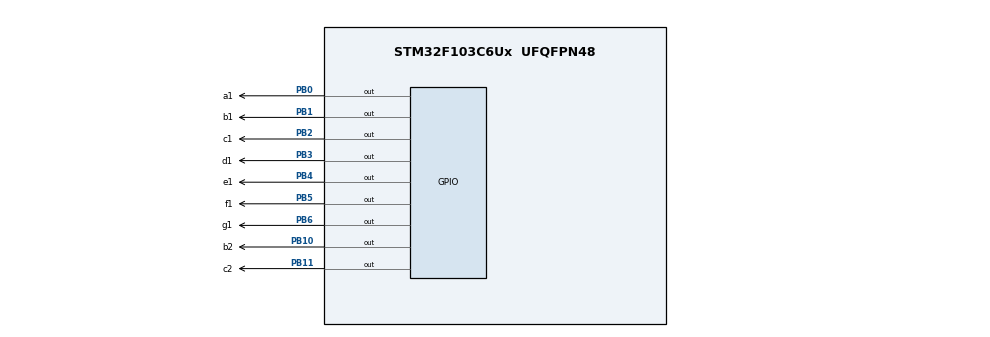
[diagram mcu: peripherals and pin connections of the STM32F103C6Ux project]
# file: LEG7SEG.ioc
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Mcu.Family=STM32F1
Mcu.Name=STM32F103C6Ux
Mcu.Package=UFQFPN48
NVIC.PriorityGroup=NVIC_PRIORITYGROUP_4
PB0.GPIO_Label=a1
PB0.Signal=GPIO_Output
PB1.GPIO_Label=b1
PB1.Signal=GPIO_Output
PB10.GPIO_Label=b2
PB10.Signal=GPIO_Output
PB11.GPIO_Label=c2
PB11.Signal=GPIO_Output
PB2.GPIO_Label=c1
PB2.Signal=GPIO_Output
PB3.GPIO_Label=d1
PB3.Signal=GPIO_Output
PB4.GPIO_Label=e1
PB4.Signal=GPIO_Output
PB5.GPIO_Label=f1
PB5.Signal=GPIO_Output
PB6.GPIO_Label=g1
PB6.Signal=GPIO_Output
ProjectManager.HeapSize=0x200
ProjectManager.StackSize=0x400
ProjectManager.TargetToolchain=STM32CubeIDE
RCC.APB1Freq_Value=8000000
RCC.APB2Freq_Value=8000000
VP_SYS_VS_ND.Mode=No_Debug
board=custom

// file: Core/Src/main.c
/* USER CODE BEGIN Header */
/**
  ******************************************************************************
  * @file           : main.c
  * @brief          : Main program body
  ******************************************************************************
  * @attention
  *
  * <h2><center>&copy; Copyright (c) 2022 STMicroelectronics.
  * All rights reserved.</center></h2>
  *
  * This software component is licensed by ST under BSD 3-Clause license,
  * the "License"; You may not use this file except in compliance with the
  * License. You may obtain a copy of the License at:
  *                        opensource.org/licenses/BSD-3-Clause
  *
  ******************************************************************************
  */
/* USER CODE END Header */
#include "main.h"

/* USER CODE BEGIN PD */
#define RED_timer 5
#define YELLOW_timer 2
#define GREEN_timer 3
/* USER CODE END PD */

void SystemClock_Config(void);
static void MX_GPIO_Init(void);

/* USER CODE BEGIN 0 */
void display7SEG(uint16_t Pin1, uint16_t Pin2, uint16_t Pin3, uint16_t Pin4, uint16_t Pin5, uint16_t Pin6, uint16_t Pin7,
				 GPIO_TypeDef* Port1, GPIO_TypeDef* Port2, GPIO_TypeDef* Port3, GPIO_TypeDef* Port4, GPIO_TypeDef* Port5, GPIO_TypeDef* Port6, GPIO_TypeDef* Port7,
				 int num) {
	switch(num) {
	case 0: //Number 0 is 0000001
		HAL_GPIO_WritePin(Port1, Pin1, RESET);
		HAL_GPIO_WritePin(Port2, Pin2, RESET);
		HAL_GPIO_WritePin(Port3, Pin3, RESET);
		HAL_GPIO_WritePin(Port4, Pin4, RESET);
		HAL_GPIO_WritePin(Port5, Pin5, RESET);
		HAL_GPIO_WritePin(Port6, Pin6, RESET);
		HAL_GPIO_WritePin(Port7, Pin7, SET);
		break;

	case 1: //Number 1 is 1001111
		HAL_GPIO_WritePin(Port1, Pin1, SET);
		HAL_GPIO_WritePin(Port2, Pin2, RESET);
		HAL_GPIO_WritePin(Port3, Pin3, RESET);
		HAL_GPIO_WritePin(Port4, Pin4, SET);
		HAL_GPIO_WritePin(Port5, Pin5, SET);
		HAL_GPIO_WritePin(Port6, Pin6, SET);
		HAL_GPIO_WritePin(Port7, Pin7, SET);
		break;

	case 2: //Number 2 is 0010010
		HAL_GPIO_WritePin(Port1, Pin1, RESET);
		HAL_GPIO_WritePin(Port2, Pin2, RESET);
		HAL_GPIO_WritePin(Port3, Pin3, SET);
		HAL_GPIO_WritePin(Port4, Pin4, RESET);
		HAL_GPIO_WritePin(Port5, Pin5, RESET);
		HAL_GPIO_WritePin(Port6, Pin6, SET);
		HAL_GPIO_WritePin(Port7, Pin7, RESET);
		break;

	case 3: //Number 3 is 0000110
		HAL_GPIO_WritePin(Port1, Pin1, RESET);
		HAL_GPIO_WritePin(Port2, Pin2, RESET);
		HAL_GPIO_WritePin(Port3, Pin3, RESET);
		HAL_GPIO_WritePin(Port4, Pin4, RESET);
		HAL_GPIO_WritePin(Port5, Pin5, SET);
		HAL_GPIO_WritePin(Port6, Pin6, SET);
		HAL_GPIO_WritePin(Port7, Pin7, RESET);
		break;

	case 4: //Number 4 is 1001100
		HAL_GPIO_WritePin(Port1, Pin1, SET);
		HAL_GPIO_WritePin(Port2, Pin2, RESET);
		HAL_GPIO_WritePin(Port3, Pin3, RESET);
		HAL_GPIO_WritePin(Port4, Pin4, SET);
		HAL_GPIO_WritePin(Port5, Pin5, SET);
		HAL_GPIO_WritePin(Port6, Pin6, RESET);
		HAL_GPIO_WritePin(Port7, Pin7, RESET);
		break;

	case 5: //Number 5 is 0100100
		HAL_GPIO_WritePin(Port1, Pin1, RESET);
		HAL_GPIO_WritePin(Port2, Pin2, SET);
		HAL_GPIO_WritePin(Port3, Pin3, RESET);
		HAL_GPIO_WritePin(Port4, Pin4, RESET);
		HAL_GPIO_WritePin(Port5, Pin5, SET);
		HAL_GPIO_WritePin(Port6, Pin6, RESET);
		HAL_GPIO_WritePin(Port7, Pin7, RESET);
		break;

	case 6: //Number 6 is 0100000
		HAL_GPIO_WritePin(Port1, Pin1, RESET);
		HAL_GPIO_WritePin(Port2, Pin2, SET);
		HAL_GPIO_WritePin(Port3, Pin3, RESET);
		HAL_GPIO_WritePin(Port4, Pin4, RESET);
		HAL_GPIO_WritePin(Port5, Pin5, RESET);
		HAL_GPIO_WritePin(Port6, Pin6, RESET);
		HAL_GPIO_WritePin(Port7, Pin7, RESET);
		break;

	case 7: //Number 7 is 0001111
		HAL_GPIO_WritePin(Port1, Pin1, RESET);
		HAL_GPIO_WritePin(Port2, Pin2, RESET);
		HAL_GPIO_WritePin(Port3, Pin3, RESET);
		HAL_GPIO_WritePin(Port4, Pin4, SET);
		HAL_GPIO_WritePin(Port5, Pin5, SET);
		HAL_GPIO_WritePin(Port6, Pin6, SET);
		HAL_GPIO_WritePin(Port7, Pin7, SET);
		break;

	case 8: //Number 8 is 0000000
		HAL_GPIO_WritePin(Port1, Pin1, RESET);
		HAL_GPIO_WritePin(Port2, Pin2, RESET);
		HAL_GPIO_WritePin(Port3, Pin3, RESET);
		HAL_GPIO_WritePin(Port4, Pin4, RESET);
		HAL_GPIO_WritePin(Port5, Pin5, RESET);
		HAL_GPIO_WritePin(Port6, Pin6, RESET);
		HAL_GPIO_WritePin(Port7, Pin7, RESET);
		break;

	case 9: //Number 9 is 0000100
		HAL_GPIO_WritePin(Port1, Pin1, RESET);
		HAL_GPIO_WritePin(Port2, Pin2, RESET);
		HAL_GPIO_WritePin(Port3, Pin3, RESET);
		HAL_GPIO_WritePin(Port4, Pin4, RESET);
		HAL_GPIO_WritePin(Port5, Pin5, SET);
		HAL_GPIO_WritePin(Port6, Pin6, RESET);
		HAL_GPIO_WritePin(Port7, Pin7, RESET);
		break;

	default: break;
	}
}
/* USER CODE END 0 */

int main(void)
{

  /* MCU Configuration--------------------------------------------------------*/

  /* Reset of all peripherals, Initializes the Flash interface and the Systick. */
  HAL_Init();

  /* Configure the system clock */
  SystemClock_Config();

  /* Initialize all configured peripherals */
  MX_GPIO_Init();

  /* Infinite loop */
  /* USER CODE BEGIN WHILE */
//4
//  int counter = 0;

  //5
  //Set the INITIAL status of each led
  int led_status1 = 1; // This is status of LEDs 1
  int led_status2 = 3; // This is status of LEDs 2
  /*
   * led_status = 1: red
   * led_status = 2: yellow
   * led_status = 3: green
   */

  //Set time for led's counter
  int red_counter1 = RED_timer;
  int yellow_counter1 = YELLOW_timer;
  int green_counter1 = GREEN_timer;

  int red_counter2 = RED_timer;
  int yellow_counter2 = YELLOW_timer;
  int green_counter2 = GREEN_timer;

  while (1) {
	  if (led_status1 == 1) //LED1 is RED
	    {
		  if (red_counter1 > 0) {
			  display7SEG(a1_Pin, b1_Pin, c1_Pin, d1_Pin, e1_Pin, f1_Pin, g1_Pin,
					  	  a1_GPIO_Port, b1_GPIO_Port, c1_GPIO_Port, d1_GPIO_Port, e1_GPIO_Port, f1_GPIO_Port, g1_GPIO_Port,
						  red_counter1--);
			  HAL_GPIO_WritePin(LED_RED1_GPIO_Port, LED_RED1_Pin, SET);
			  HAL_GPIO_WritePin(LED_YELLOW1_GPIO_Port, LED_YELLOW1_Pin, RESET);
			  HAL_GPIO_WritePin(LED_GREEN1_GPIO_Port, LED_GREEN1_Pin, RESET);
		  } else {
			  display7SEG(a1_Pin, b1_Pin, c1_Pin, d1_Pin, e1_Pin, f1_Pin, g1_Pin,
						  a1_GPIO_Port, b1_GPIO_Port, c1_GPIO_Port, d1_GPIO_Port, e1_GPIO_Port, f1_GPIO_Port, g1_GPIO_Port,
						  red_counter1);

			  //Switch LED1 from RED to GREEN and reset red_counter
			  red_counter1 = RED_timer;
			  led_status1 = 3;
		  }
	  }

	  else if (led_status1 == 2) //LED1 is YELLOW
	  {
		  if (yellow_counter1 > 0) {
			  display7SEG(a1_Pin, b1_Pin, c1_Pin, d1_Pin, e1_Pin, f1_Pin, g1_Pin,
						  a1_GPIO_Port, b1_GPIO_Port, c1_GPIO_Port, d1_GPIO_Port, e1_GPIO_Port, f1_GPIO_Port, g1_GPIO_Port,
						  yellow_counter1--);
			  HAL_GPIO_WritePin(LED_YELLOW1_GPIO_Port, LED_YELLOW1_Pin, SET);
			  HAL_GPIO_WritePin(LED_GREEN1_GPIO_Port, LED_GREEN1_Pin, RESET);
			  HAL_GPIO_WritePin(LED_RED1_GPIO_Port, LED_RED1_Pin, RESET);
		  } else {
			  display7SEG(a1_Pin, b1_Pin, c1_Pin, d1_Pin, e1_Pin, f1_Pin, g1_Pin,
						  a1_GPIO_Port, b1_GPIO_Port, c1_GPIO_Port, d1_GPIO_Port, e1_GPIO_Port, f1_GPIO_Port, g1_GPIO_Port,
						  yellow_counter1);

			  //Switch LED1 from YELLOW to RED and reset yelloW_counter
			  yellow_counter1 = YELLOW_timer;
			  led_status1 = 1;
		  }
	  }

	  else if (led_status1 == 3) //LED1 is GREEN
	  {
		  if (green_counter1 > 0) {
			  display7SEG(a1_Pin, b1_Pin, c1_Pin, d1_Pin, e1_Pin, f1_Pin, g1_Pin,
						  a1_GPIO_Port, b1_GPIO_Port, c1_GPIO_Port, d1_GPIO_Port, e1_GPIO_Port, f1_GPIO_Port, g1_GPIO_Port,
						  green_counter1--);
			  HAL_GPIO_WritePin(LED_GREEN1_GPIO_Port, LED_GREEN1_Pin, SET);
			  HAL_GPIO_WritePin(LED_YELLOW1_GPIO_Port, LED_YELLOW1_Pin, RESET);
			  HAL_GPIO_WritePin(LED_RED1_GPIO_Port, LED_RED1_Pin, RESET);
		  } else {
			  display7SEG(a1_Pin, b1_Pin, c1_Pin, d1_Pin, e1_Pin, f1_Pin, g1_Pin,
						  a1_GPIO_Port, b1_GPIO_Port, c1_GPIO_Port, d1_GPIO_Port, e1_GPIO_Port, f1_GPIO_Port, g1_GPIO_Port,
						  green_counter1);

			  //Switch LED1 from GREEN to YELLOW and reset green_counter
			  green_counter1 = GREEN_timer;
			  led_status1 = 2;
		  }
	  }

	  if (led_status2 == 1) //LED2 is RED
	  {
		  if (red_counter2 > 0) {
			  display7SEG(a2_Pin, b2_Pin, c2_Pin, d2_Pin, e2_Pin, f2_Pin, g2_Pin,
					  	  a2_GPIO_Port, b2_GPIO_Port, c2_GPIO_Port, d2_GPIO_Port, e2_GPIO_Port, f2_GPIO_Port, g2_GPIO_Port,
						  red_counter2--);
			  HAL_GPIO_WritePin(LED_RED2_GPIO_Port, LED_RED2_Pin, SET);
			  HAL_GPIO_WritePin(LED_GREEN2_GPIO_Port, LED_GREEN2_Pin, RESET);
			  HAL_GPIO_WritePin(LED_YELLOW2_GPIO_Port, LED_YELLOW2_Pin, RESET);

		  } else {
			  display7SEG(a2_Pin, b2_Pin, c2_Pin, d2_Pin, e2_Pin, f2_Pin, g2_Pin,
						  a2_GPIO_Port, b2_GPIO_Port, c2_GPIO_Port, d2_GPIO_Port, e2_GPIO_Port, f2_GPIO_Port, g2_GPIO_Port,
						  red_counter2);

			  //Switch LED2 from RED to GREEN and reset red_counter
			  red_counter2 = RED_timer;
			  led_status2 = 3;
		  }
	  }

	  else if (led_status2 == 2) //LED2 is YELLOW
	  {
		  if (yellow_counter2 > 0) {
			  display7SEG(a2_Pin, b2_Pin, c2_Pin, d2_Pin, e2_Pin, f2_Pin, g2_Pin,
					  	  a2_GPIO_Port, b2_GPIO_Port, c2_GPIO_Port, d2_GPIO_Port, e2_GPIO_Port, f2_GPIO_Port, g2_GPIO_Port,
						  yellow_counter2--);
			  HAL_GPIO_WritePin(LED_YELLOW2_GPIO_Port, LED_YELLOW2_Pin, SET);
			  HAL_GPIO_WritePin(LED_RED2_GPIO_Port, LED_RED2_Pin, RESET);
			  HAL_GPIO_WritePin(LED_GREEN2_GPIO_Port, LED_GREEN2_Pin, RESET);

		  } else {
			  display7SEG(a2_Pin, b2_Pin, c2_Pin, d2_Pin, e2_Pin, f2_Pin, g2_Pin,
						  a2_GPIO_Port, b2_GPIO_Port, c2_GPIO_Port, d2_GPIO_Port, e2_GPIO_Port, f2_GPIO_Port, g2_GPIO_Port,
						  yellow_counter2);

			  //Switch LED2 from YELLOW to RED and reset yellow_counter
			  yellow_counter2 = YELLOW_timer;
			  led_status2 = 1;
		  }
	  }

	  else if (led_status2 == 3) ////LED2 is GREEN
	  {
		  if (green_counter2 > 0) {
			  display7SEG(a2_Pin, b2_Pin, c2_Pin, d2_Pin, e2_Pin, f2_Pin, g2_Pin,
						  a2_GPIO_Port, b2_GPIO_Port, c2_GPIO_Port, d2_GPIO_Port, e2_GPIO_Port, f2_GPIO_Port, g2_GPIO_Port,
						  green_counter2--);
			  HAL_GPIO_WritePin(LED_GREEN2_GPIO_Port, LED_GREEN2_Pin, SET);
			  HAL_GPIO_WritePin(LED_RED2_GPIO_Port, LED_RED2_Pin, RESET);
			  HAL_GPIO_WritePin(LED_YELLOW2_GPIO_Port, LED_YELLOW2_Pin, RESET);

		  } else {
			  display7SEG(a2_Pin, b2_Pin, c2_Pin, d2_Pin, e2_Pin, f2_Pin, g2_Pin,
						  a2_GPIO_Port, b2_GPIO_Port, c2_GPIO_Port, d2_GPIO_Port, e2_GPIO_Port, f2_GPIO_Port, g2_GPIO_Port,
						  green_counter2);

			  //Switch LED2 from GREEN to YELLOW and reset green_counter
			  green_counter2 = GREEN_timer;
			  led_status2 = 2;
		  }
	  }

	  HAL_Delay(1000);
  	  /* USER CODE END WHILE */

    }
}

void SystemClock_Config(void)
{
  RCC_OscInitTypeDef RCC_OscInitStruct = {0};
  RCC_ClkInitTypeDef RCC_ClkInitStruct = {0};

  /** Initializes the RCC Oscillators according to the specified parameters
  * in the RCC_OscInitTypeDef structure.
  */
  RCC_OscInitStruct.OscillatorType = RCC_OSCILLATORTYPE_HSI;
  RCC_OscInitStruct.HSIState = RCC_HSI_ON;
  RCC_OscInitStruct.HSICalibrationValue = RCC_HSICALIBRATION_DEFAULT;
  RCC_OscInitStruct.PLL.PLLState = RCC_PLL_NONE;
  if (HAL_RCC_OscConfig(&RCC_OscInitStruct) != HAL_OK)
  {
    Error_Handler();
  }
  /** Initializes the CPU, AHB and APB buses clocks
  */
  RCC_ClkInitStruct.ClockType = RCC_CLOCKTYPE_HCLK|RCC_CLOCKTYPE_SYSCLK
                              |RCC_CLOCKTYPE_PCLK1|RCC_CLOCKTYPE_PCLK2;
  RCC_ClkInitStruct.SYSCLKSource = RCC_SYSCLKSOURCE_HSI;
  RCC_ClkInitStruct.AHBCLKDivider = RCC_SYSCLK_DIV1;
  RCC_ClkInitStruct.APB1CLKDivider = RCC_HCLK_DIV1;
  RCC_ClkInitStruct.APB2CLKDivider = RCC_HCLK_DIV1;

  if (HAL_RCC_ClockConfig(&RCC_ClkInitStruct, FLASH_LATENCY_0) != HAL_OK)
  {
    Error_Handler();
  }
}

static void MX_GPIO_Init(void)
{
  GPIO_InitTypeDef GPIO_InitStruct = {0};

  /* GPIO Ports Clock Enable */
  __HAL_RCC_GPIOA_CLK_ENABLE();
  __HAL_RCC_GPIOB_CLK_ENABLE();

  /*Configure GPIO pin Output Level */
  HAL_GPIO_WritePin(GPIOA, LED_RED1_Pin|LED_YELLOW1_Pin|LED_GREEN1_Pin|LED_RED2_Pin
                          |LED_YELLOW2_Pin|LED_GREEN2_Pin, GPIO_PIN_RESET);

  /*Configure GPIO pin Output Level */
  HAL_GPIO_WritePin(GPIOB, a1_Pin|b1_Pin|c1_Pin|b2_Pin
                          |c2_Pin|d2_Pin|e2_Pin|f2_Pin
                          |g2_Pin|d1_Pin|e1_Pin|f1_Pin
                          |g1_Pin|a2_Pin, GPIO_PIN_RESET);

  /*Configure GPIO pins : LED_RED1_Pin LED_YELLOW1_Pin LED_GREEN1_Pin LED_RED2_Pin
                           LED_YELLOW2_Pin LED_GREEN2_Pin */
  GPIO_InitStruct.Pin = LED_RED1_Pin|LED_YELLOW1_Pin|LED_GREEN1_Pin|LED_RED2_Pin
                          |LED_YELLOW2_Pin|LED_GREEN2_Pin;
  GPIO_InitStruct.Mode = GPIO_MODE_OUTPUT_PP;
  GPIO_InitStruct.Pull = GPIO_NOPULL;
  GPIO_InitStruct.Speed = GPIO_SPEED_FREQ_LOW;
  HAL_GPIO_Init(GPIOA, &GPIO_InitStruct);

  /*Configure GPIO pins : a1_Pin b1_Pin c1_Pin b2_Pin
                           c2_Pin d2_Pin e2_Pin f2_Pin
                           g2_Pin d1_Pin e1_Pin f1_Pin
                           g1_Pin a2_Pin */
  GPIO_InitStruct.Pin = a1_Pin|b1_Pin|c1_Pin|b2_Pin
                          |c2_Pin|d2_Pin|e2_Pin|f2_Pin
                          |g2_Pin|d1_Pin|e1_Pin|f1_Pin
                          |g1_Pin|a2_Pin;
  GPIO_InitStruct.Mode = GPIO_MODE_OUTPUT_PP;
  GPIO_InitStruct.Pull = GPIO_NOPULL;
  GPIO_InitStruct.Speed = GPIO_SPEED_FREQ_LOW;
  HAL_GPIO_Init(GPIOB, &GPIO_InitStruct);

}

void Error_Handler(void)
{
  __disable_irq();
  while (1)
  {
  }
}

/************************ (C) COPYRIGHT STMicroelectronics *****END OF FILE****/
